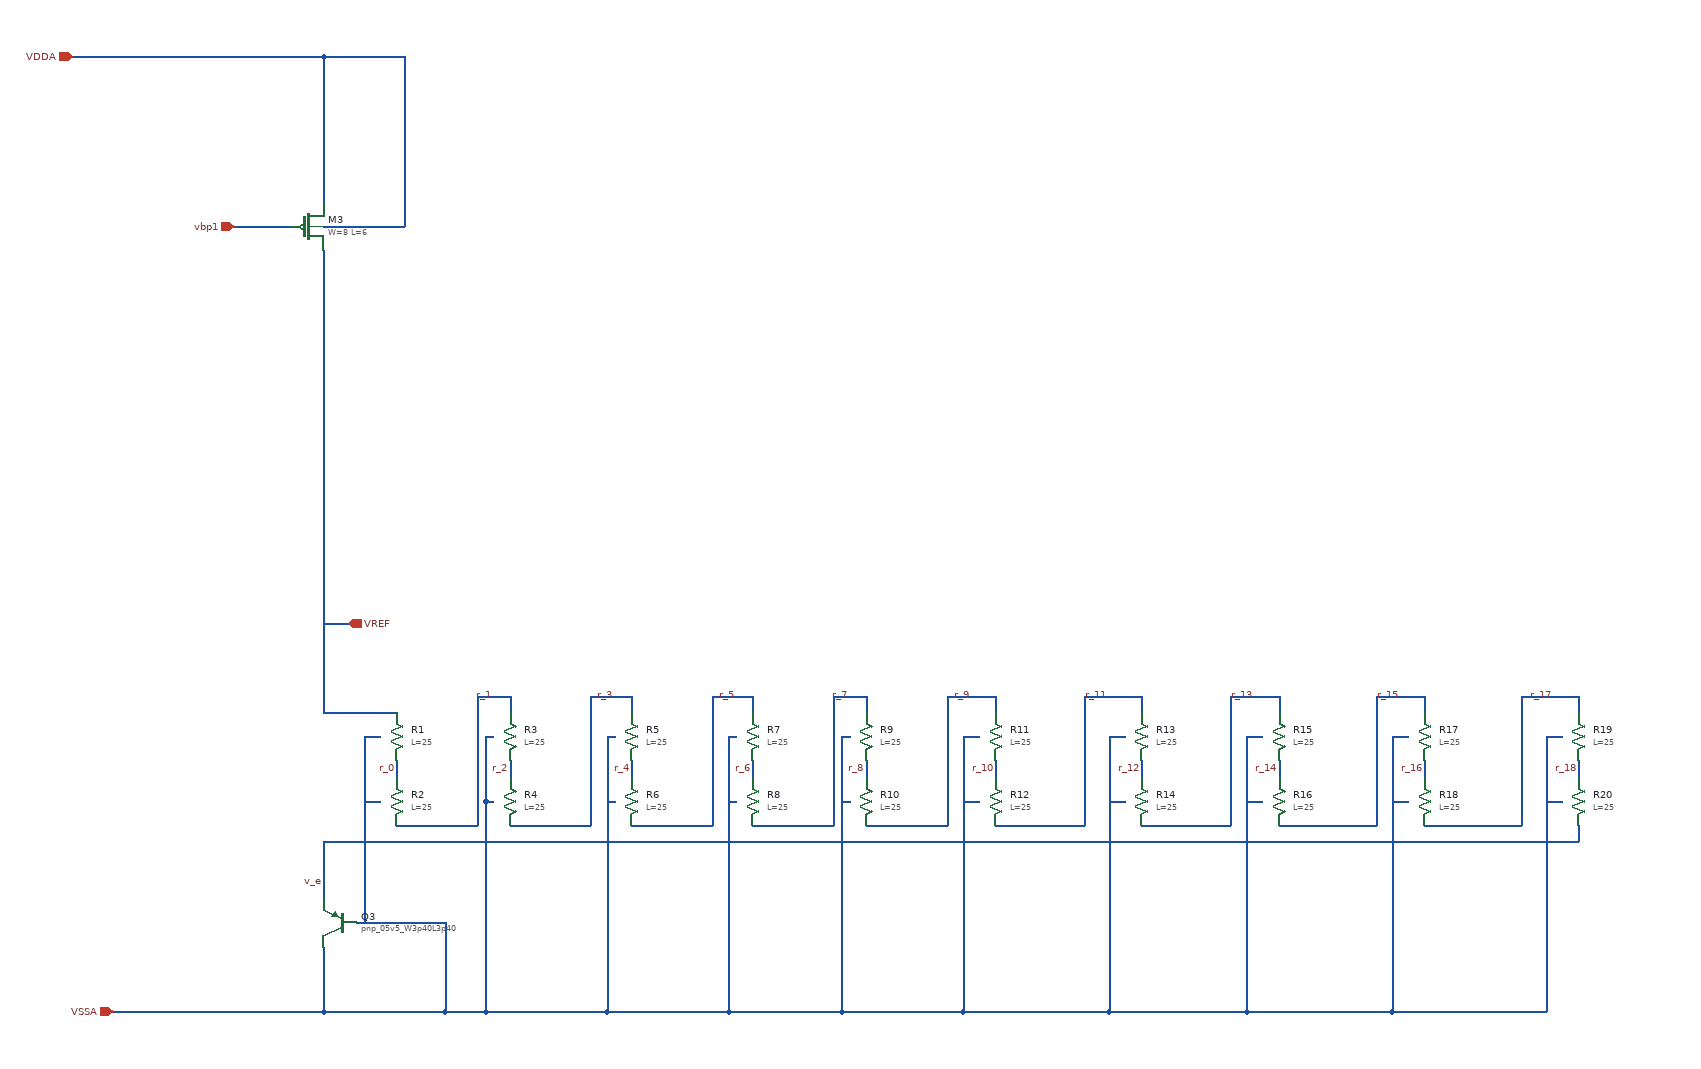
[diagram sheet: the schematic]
v {xschem version=3.4.8RC file_version=1.3}
G {}
K {}
V {}
S {}
F {}
E {}
N 1560 -1220 1560 -1200 {lab=VREF}
N 1560 -1350 1560 -1280 {lab=VDDA}
N 1560 -1460 1560 -1450 {lab=VDDA}
N 1560 -1250 1660 -1250 {lab=VDDA}
N 1660 -1360 1660 -1250 {lab=VDDA}
N 1560 -1460 1660 -1460 {lab=VDDA}
N 1560 -460 1560 -420 {lab=v_e}
N 1560 -360 1560 -280 {lab=VSSA}
N 1420 -280 1560 -280 {lab=VSSA}
N 1600 -390 1710 -390 {lab=VSSA}
N 1710 -390 1710 -280 {lab=VSSA}
N 1560 -280 1710 -280 {lab=VSSA}
N 1450 -1250 1520 -1250 {lab=vbp1}
N 1560 -890 1560 -750 {lab=VREF}
N 1560 -690 1560 -660 {lab=VREF}
N 1300 -280 1410 -280 {lab=VSSA}
N 1410 -280 1420 -280 {lab=VSSA}
N 1560 -1200 1560 -890 {lab=VREF}
N 1250 -1460 1560 -1460 {lab=VDDA}
N 1660 -1460 1660 -1360 {lab=VDDA}
N 1560 -1450 1560 -1350 {lab=VDDA}
N 1560 -750 1560 -690 {lab=VREF}
N 1560 -760 1590 -760 {lab=VREF}
N 1560 -650 1650 -650 {lab=VREF}
N 1560 -660 1560 -650 {lab=VREF}
N 1610 -620 1630 -620 {lab=VSSA}
N 1610 -620 1610 -390 {lab=VSSA}
N 1610 -540 1630 -540 {lab=VSSA}
N 1940 -590 1940 -570 {lab=r_4}
N 1940 -670 1940 -650 {lab=r_3}
N 1890 -670 1940 -670 {lab=r_3}
N 1890 -670 1890 -510 {lab=r_3}
N 1790 -510 1890 -510 {lab=r_3}
N 1790 -590 1790 -570 {lab=r_2}
N 1790 -670 1790 -650 {lab=r_1}
N 1750 -670 1790 -670 {lab=r_1}
N 1750 -670 1750 -510 {lab=r_1}
N 1650 -510 1750 -510 {lab=r_1}
N 1650 -590 1650 -570 {lab=r_0}
N 1940 -510 2030 -510 {lab=r_5}
N 2030 -510 2040 -510 {lab=r_5}
N 2040 -670 2040 -510 {lab=r_5}
N 2040 -670 2090 -670 {lab=r_5}
N 2090 -670 2090 -650 {lab=r_5}
N 2090 -590 2090 -570 {lab=r_6}
N 2090 -510 2190 -510 {lab=r_7}
N 2190 -670 2190 -510 {lab=r_7}
N 2190 -670 2230 -670 {lab=r_7}
N 2230 -670 2230 -650 {lab=r_7}
N 2230 -590 2230 -570 {lab=r_8}
N 1760 -540 1770 -540 {lab=VSSA}
N 1760 -540 1760 -390 {lab=VSSA}
N 1760 -390 1760 -280 {lab=VSSA}
N 1710 -280 1760 -280 {lab=VSSA}
N 1760 -620 1770 -620 {lab=VSSA}
N 1760 -620 1760 -540 {lab=VSSA}
N 1910 -620 1920 -620 {lab=VSSA}
N 1910 -620 1910 -280 {lab=VSSA}
N 1760 -280 1910 -280 {lab=VSSA}
N 1910 -540 1920 -540 {lab=VSSA}
N 2060 -620 2070 -620 {lab=VSSA}
N 2060 -620 2060 -280 {lab=VSSA}
N 1910 -280 2060 -280 {lab=VSSA}
N 2060 -540 2070 -540 {lab=VSSA}
N 2200 -620 2210 -620 {lab=VSSA}
N 2200 -620 2200 -280 {lab=VSSA}
N 2060 -280 2200 -280 {lab=VSSA}
N 2200 -540 2210 -540 {lab=VSSA}
N 1560 -490 1560 -460 {lab=v_e}
N 2230 -510 2330 -510 {lab=r_9}
N 2330 -670 2330 -510 {lab=r_9}
N 2330 -670 2390 -670 {lab=r_9}
N 2390 -670 2390 -650 {lab=r_9}
N 2390 -590 2390 -570 {lab=r_10}
N 2390 -510 2500 -510 {lab=r_11}
N 2500 -670 2500 -510 {lab=r_11}
N 2500 -670 2570 -670 {lab=r_11}
N 2570 -670 2570 -650 {lab=r_11}
N 2570 -590 2570 -570 {lab=r_12}
N 2570 -510 2680 -510 {lab=r_13}
N 2680 -670 2680 -510 {lab=r_13}
N 2680 -670 2740 -670 {lab=r_13}
N 2740 -670 2740 -650 {lab=r_13}
N 2740 -590 2740 -570 {lab=r_14}
N 2740 -510 2860 -510 {lab=r_15}
N 2860 -670 2860 -510 {lab=r_15}
N 2860 -670 2920 -670 {lab=r_15}
N 2920 -670 2920 -650 {lab=r_15}
N 2920 -590 2920 -570 {lab=r_16}
N 2920 -510 3040 -510 {lab=r_17}
N 3040 -670 3040 -510 {lab=r_17}
N 3040 -670 3110 -670 {lab=r_17}
N 3110 -670 3110 -650 {lab=r_17}
N 3110 -590 3110 -570 {lab=r_8}
N 2350 -620 2370 -620 {lab=VSSA}
N 2350 -620 2350 -280 {lab=VSSA}
N 2200 -280 2350 -280 {lab=VSSA}
N 2350 -540 2370 -540 {lab=VSSA}
N 2530 -620 2550 -620 {lab=VSSA}
N 2530 -620 2530 -280 {lab=VSSA}
N 2350 -280 2530 -280 {lab=VSSA}
N 2530 -540 2550 -540 {lab=VSSA}
N 2700 -620 2720 -620 {lab=VSSA}
N 2700 -620 2700 -280 {lab=VSSA}
N 2530 -280 2700 -280 {lab=VSSA}
N 2700 -540 2720 -540 {lab=VSSA}
N 2880 -620 2900 -620 {lab=VSSA}
N 2880 -620 2880 -280 {lab=VSSA}
N 2700 -280 2880 -280 {lab=VSSA}
N 2880 -540 2900 -540 {lab=VSSA}
N 3070 -620 3090 -620 {lab=VSSA}
N 3070 -620 3070 -280 {lab=VSSA}
N 2880 -280 3070 -280 {lab=VSSA}
N 3070 -540 3090 -540 {lab=VSSA}
N 1560 -490 3110 -490 {lab=v_e}
N 3110 -510 3110 -490 {lab=v_e}
C {/usr/local/share/pdk/sky130B/libs.tech/xschem/sky130_fd_pr/pnp_05v5.sym} 1580 -390 0 1 {name=Q3
model=pnp_05v5_W3p40L3p40
m=8
spiceprefix=X
}
C {/usr/local/share/pdk/sky130B/libs.tech/xschem/sky130_fd_pr/pfet_01v8_lvt.sym} 1540 -1250 0 0 {name=M3
W=8
L=6
nf=1
mult=1
ad="expr('int((@nf + 1)/2) * @W / @nf * 0.29')"
pd="expr('2*int((@nf + 1)/2) * (@W / @nf + 0.29)')"
as="expr('int((@nf + 2)/2) * @W / @nf * 0.29')"
ps="expr('2*int((@nf + 2)/2) * (@W / @nf + 0.29)')"
nrd="expr('0.29 / @W ')" nrs="expr('0.29 / @W ')"
sa=0 sb=0 sd=0
model=pfet_01v8_lvt
spiceprefix=X
}
C {ipin.sym} 1300 -280 0 0 {name=p2 lab=VSSA}
C {opin.sym} 1590 -760 0 0 {name=p4 lab=VREF}
C {ipin.sym} 1250 -1460 0 0 {name=p1 lab=VDDA
}
C {ipin.sym} 1450 -1250 0 0 {name=p5 lab=vbp1}
C {lab_wire.sym} 1560 -440 0 0 {name=p3 sig_type=std_logic lab=v_e}
C {/usr/local/share/pdk/sky130A/libs.tech/xschem/sky130_fd_pr/res_high_po_0p35.sym} 1650 -620 0 0 {name=R1
L=25
model=res_high_po_0p35
spiceprefix=X
mult=1}
C {/usr/local/share/pdk/sky130A/libs.tech/xschem/sky130_fd_pr/res_high_po_0p35.sym} 1650 -540 0 0 {name=R2
L=25
model=res_high_po_0p35
spiceprefix=X
mult=1}
C {/usr/local/share/pdk/sky130A/libs.tech/xschem/sky130_fd_pr/res_high_po_0p35.sym} 1790 -620 0 0 {name=R3
L=25
model=res_high_po_0p35
spiceprefix=X
mult=1}
C {/usr/local/share/pdk/sky130A/libs.tech/xschem/sky130_fd_pr/res_high_po_0p35.sym} 1790 -540 0 0 {name=R4
L=25
model=res_high_po_0p35
spiceprefix=X
mult=1}
C {/usr/local/share/pdk/sky130A/libs.tech/xschem/sky130_fd_pr/res_high_po_0p35.sym} 1940 -620 0 0 {name=R5
L=25
model=res_high_po_0p35
spiceprefix=X
mult=1}
C {/usr/local/share/pdk/sky130A/libs.tech/xschem/sky130_fd_pr/res_high_po_0p35.sym} 1940 -540 0 0 {name=R6
L=25
model=res_high_po_0p35
spiceprefix=X
mult=1}
C {/usr/local/share/pdk/sky130A/libs.tech/xschem/sky130_fd_pr/res_high_po_0p35.sym} 2090 -620 0 0 {name=R7
L=25
model=res_high_po_0p35
spiceprefix=X
mult=1}
C {/usr/local/share/pdk/sky130A/libs.tech/xschem/sky130_fd_pr/res_high_po_0p35.sym} 2090 -540 0 0 {name=R8
L=25
model=res_high_po_0p35
spiceprefix=X
mult=1}
C {/usr/local/share/pdk/sky130A/libs.tech/xschem/sky130_fd_pr/res_high_po_0p35.sym} 2230 -620 0 0 {name=R9
L=25
model=res_high_po_0p35
spiceprefix=X
mult=1}
C {/usr/local/share/pdk/sky130A/libs.tech/xschem/sky130_fd_pr/res_high_po_0p35.sym} 2230 -540 0 0 {name=R10
L=25
model=res_high_po_0p35
spiceprefix=X
mult=1}
C {lab_wire.sym} 1650 -580 0 0 {name=p6 sig_type=std_logic lab=r_0}
C {lab_wire.sym} 1770 -670 0 0 {name=p7 sig_type=std_logic lab=r_1}
C {lab_wire.sym} 1920 -670 0 0 {name=p8 sig_type=std_logic lab=r_3}
C {lab_wire.sym} 2070 -670 0 0 {name=p9 sig_type=std_logic lab=r_5}
C {lab_wire.sym} 2210 -670 0 0 {name=p10 sig_type=std_logic lab=r_7}
C {lab_wire.sym} 1790 -580 0 0 {name=p11 sig_type=std_logic lab=r_2}
C {lab_wire.sym} 1940 -580 0 0 {name=p12 sig_type=std_logic lab=r_4}
C {lab_wire.sym} 2090 -580 0 0 {name=p13 sig_type=std_logic lab=r_6}
C {lab_wire.sym} 2230 -580 0 0 {name=p14 sig_type=std_logic lab=r_8}
C {/usr/local/share/pdk/sky130A/libs.tech/xschem/sky130_fd_pr/res_high_po_0p35.sym} 2390 -620 0 0 {name=R11
L=25
model=res_high_po_0p35
spiceprefix=X
mult=1}
C {/usr/local/share/pdk/sky130A/libs.tech/xschem/sky130_fd_pr/res_high_po_0p35.sym} 2390 -540 0 0 {name=R12
L=25
model=res_high_po_0p35
spiceprefix=X
mult=1}
C {/usr/local/share/pdk/sky130A/libs.tech/xschem/sky130_fd_pr/res_high_po_0p35.sym} 2570 -620 0 0 {name=R13
L=25
model=res_high_po_0p35
spiceprefix=X
mult=1}
C {/usr/local/share/pdk/sky130A/libs.tech/xschem/sky130_fd_pr/res_high_po_0p35.sym} 2570 -540 0 0 {name=R14
L=25
model=res_high_po_0p35
spiceprefix=X
mult=1}
C {/usr/local/share/pdk/sky130A/libs.tech/xschem/sky130_fd_pr/res_high_po_0p35.sym} 2740 -620 0 0 {name=R15
L=25
model=res_high_po_0p35
spiceprefix=X
mult=1}
C {/usr/local/share/pdk/sky130A/libs.tech/xschem/sky130_fd_pr/res_high_po_0p35.sym} 2740 -540 0 0 {name=R16
L=25
model=res_high_po_0p35
spiceprefix=X
mult=1}
C {/usr/local/share/pdk/sky130A/libs.tech/xschem/sky130_fd_pr/res_high_po_0p35.sym} 2920 -620 0 0 {name=R17
L=25
model=res_high_po_0p35
spiceprefix=X
mult=1}
C {/usr/local/share/pdk/sky130A/libs.tech/xschem/sky130_fd_pr/res_high_po_0p35.sym} 2920 -540 0 0 {name=R18
L=25
model=res_high_po_0p35
spiceprefix=X
mult=1}
C {/usr/local/share/pdk/sky130A/libs.tech/xschem/sky130_fd_pr/res_high_po_0p35.sym} 3110 -620 0 0 {name=R19
L=25
model=res_high_po_0p35
spiceprefix=X
mult=1}
C {/usr/local/share/pdk/sky130A/libs.tech/xschem/sky130_fd_pr/res_high_po_0p35.sym} 3110 -540 0 0 {name=R20
L=25
model=res_high_po_0p35
spiceprefix=X
mult=1}
C {lab_wire.sym} 2360 -670 0 0 {name=p15 sig_type=std_logic lab=r_9}
C {lab_wire.sym} 2390 -580 0 0 {name=p16 sig_type=std_logic lab=r_10}
C {lab_wire.sym} 2530 -670 0 0 {name=p17 sig_type=std_logic lab=r_11}
C {lab_wire.sym} 2570 -580 0 0 {name=p18 sig_type=std_logic lab=r_12}
C {lab_wire.sym} 2710 -670 0 0 {name=p19 sig_type=std_logic lab=r_13}
C {lab_wire.sym} 2740 -580 0 0 {name=p20 sig_type=std_logic lab=r_14}
C {lab_wire.sym} 2890 -670 0 0 {name=p21 sig_type=std_logic lab=r_15}
C {lab_wire.sym} 2920 -580 0 0 {name=p22 sig_type=std_logic lab=r_16}
C {lab_wire.sym} 3080 -670 0 0 {name=p23 sig_type=std_logic lab=r_17}
C {lab_wire.sym} 3110 -580 0 0 {name=p24 sig_type=std_logic lab=r_18}
